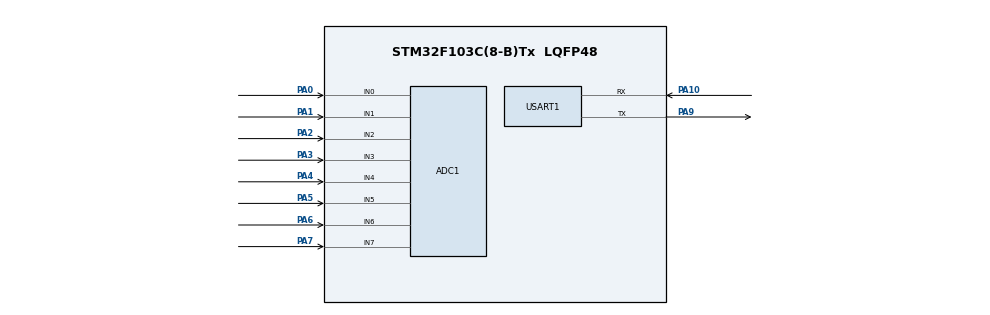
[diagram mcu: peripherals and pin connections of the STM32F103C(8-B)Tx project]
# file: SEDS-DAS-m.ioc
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ADC1.Channel=ADC_CHANNEL_6
ADC1.Channel-1\#ChannelRegularConversion=ADC_CHANNEL_0
ADC1.Channel-2\#ChannelRegularConversion=ADC_CHANNEL_0
ADC1.Channel-3\#ChannelRegularConversion=ADC_CHANNEL_0
ADC1.Channel-4\#ChannelRegularConversion=ADC_CHANNEL_0
ADC1.Channel-5\#ChannelRegularConversion=ADC_CHANNEL_0
ADC1.Channel-6\#ChannelRegularConversion=ADC_CHANNEL_0
ADC1.Channel-7\#ChannelRegularConversion=ADC_CHANNEL_0
ADC1.Channel-8\#ChannelRegularConversion=ADC_CHANNEL_0
ADC1.ContinuousConvMode=DISABLE
ADC1.EnableRegularConversion=ENABLE
ADC1.NbrOfConversion=8
ADC1.NbrOfConversionFlag=1
ADC1.Rank-1\#ChannelRegularConversion=1
ADC1.Rank-2\#ChannelRegularConversion=2
ADC1.Rank-3\#ChannelRegularConversion=3
ADC1.Rank-4\#ChannelRegularConversion=4
ADC1.Rank-5\#ChannelRegularConversion=5
ADC1.Rank-6\#ChannelRegularConversion=6
ADC1.Rank-7\#ChannelRegularConversion=7
ADC1.Rank-8\#ChannelRegularConversion=8
ADC1.SamplingTime-1\#ChannelRegularConversion=ADC_SAMPLETIME_1CYCLE_5
ADC1.SamplingTime-2\#ChannelRegularConversion=ADC_SAMPLETIME_1CYCLE_5
ADC1.SamplingTime-3\#ChannelRegularConversion=ADC_SAMPLETIME_1CYCLE_5
ADC1.SamplingTime-4\#ChannelRegularConversion=ADC_SAMPLETIME_1CYCLE_5
ADC1.SamplingTime-5\#ChannelRegularConversion=ADC_SAMPLETIME_1CYCLE_5
ADC1.SamplingTime-6\#ChannelRegularConversion=ADC_SAMPLETIME_1CYCLE_5
ADC1.SamplingTime-7\#ChannelRegularConversion=ADC_SAMPLETIME_1CYCLE_5
ADC1.SamplingTime-8\#ChannelRegularConversion=ADC_SAMPLETIME_1CYCLE_5
ADC1.master=1
Dma.ADC1.0.Direction=DMA_PERIPH_TO_MEMORY
Dma.ADC1.0.Instance=DMA1_Channel1
Dma.ADC1.0.MemDataAlignment=DMA_MDATAALIGN_BYTE
Dma.ADC1.0.MemInc=DMA_MINC_DISABLE
Dma.ADC1.0.Mode=DMA_NORMAL
Dma.ADC1.0.PeriphDataAlignment=DMA_PDATAALIGN_BYTE
Dma.ADC1.0.PeriphInc=DMA_PINC_DISABLE
Dma.ADC1.0.Priority=DMA_PRIORITY_LOW
Dma.Request0=ADC1
FREERTOS.Tasks01=defaultTask,0,128,StartDefaultTask;pingBack,0,128,StartTask02;idleADCSample,-3,128,StartTask03
Mcu.Family=STM32F1
Mcu.Name=STM32F103C(8-B)Tx
Mcu.Package=LQFP48
NVIC.ADC1_2_IRQn=true\:5\:0\:false
NVIC.DMA1_Channel1_IRQn=true\:5\:0\:false
NVIC.PriorityGroup=NVIC_PRIORITYGROUP_4
NVIC.TIM1_UP_IRQn=true\:5\:0\:false
PA0-WKUP.Signal=ADCx_IN0
PA1.Signal=ADCx_IN1
PA10.Mode=Asynchronous
PA10.Signal=USART1_RX
PA2.Signal=ADCx_IN2
PA3.Signal=ADCx_IN3
PA4.Signal=ADCx_IN4
PA5.Signal=ADCx_IN5
PA6.Signal=ADCx_IN6
PA7.Signal=ADCx_IN7
PA9.Mode=Asynchronous
PA9.Signal=USART1_TX
ProjectManager.TargetToolchain=MDK-ARM 4.73
RCC.ADCPresc=RCC_ADCPCLK2_DIV6
RCC.AHBFreq_Value=64000000
RCC.APB1CLKDivider=RCC_HCLK_DIV2
RCC.APB1Freq_Value=32000000
RCC.APB1TimFreq_Value=64000000
RCC.APB2Freq_Value=64000000
RCC.APB2TimFreq_Value=64000000
RCC.HCLKFreq_Value=64000000
RCC.SYSCLKFreq_VALUE=64000000
RCC.SYSCLKSource=RCC_SYSCLKSOURCE_PLLCLK
RCC.USBFreq_Value=64000000
SH.ADCx_IN0.0=ADC1_IN0,IN0
SH.ADCx_IN1.0=ADC1_IN1,IN1
SH.ADCx_IN2.0=ADC1_IN2,IN2
SH.ADCx_IN3.0=ADC1_IN3,IN3
SH.ADCx_IN4.0=ADC1_IN4,IN4
SH.ADCx_IN5.0=ADC1_IN5,IN5
SH.ADCx_IN6.0=ADC1_IN6,IN6
SH.ADCx_IN7.0=ADC1_IN7,IN7
TIM1.Period=50000
USART1.Parity-Asynchronous=UART_PARITY_EVEN
USART1.WordLength-Asynchronous=UART_WORDLENGTH_9B
VP_FREERTOS_VS_ENABLE.Mode=Enabled
VP_TIM1_VS_ClockSourceINT.Mode=Internal

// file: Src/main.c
/**
  ******************************************************************************
  * File Name          : main.c
  * Date               : 04/04/2015 04:53:10
  * Description        : Main program body
  ******************************************************************************
  *
  * COPYRIGHT(c) 2015 STMicroelectronics
  *
  * Redistribution and use in source and binary forms, with or without modification,
  * are permitted provided that the following conditions are met:
  *   1. Redistributions of source code must retain the above copyright notice,
  *      this list of conditions and the following disclaimer.
  *   2. Redistributions in binary form must reproduce the above copyright notice,
  *      this list of conditions and the following disclaimer in the documentation
  *      and/or other materials provided with the distribution.
  *   3. Neither the name of STMicroelectronics nor the names of its contributors
  *      may be used to endorse or promote products derived from this software
  *      without specific prior written permission.
  *
  * THIS SOFTWARE IS PROVIDED BY THE COPYRIGHT HOLDERS AND CONTRIBUTORS "AS IS"
  * AND ANY EXPRESS OR IMPLIED WARRANTIES, INCLUDING, BUT NOT LIMITED TO, THE
  * IMPLIED WARRANTIES OF MERCHANTABILITY AND FITNESS FOR A PARTICULAR PURPOSE ARE
  * DISCLAIMED. IN NO EVENT SHALL THE COPYRIGHT HOLDER OR CONTRIBUTORS BE LIABLE
  * FOR ANY DIRECT, INDIRECT, INCIDENTAL, SPECIAL, EXEMPLARY, OR CONSEQUENTIAL
  * DAMAGES (INCLUDING, BUT NOT LIMITED TO, PROCUREMENT OF SUBSTITUTE GOODS OR
  * SERVICES; LOSS OF USE, DATA, OR PROFITS; OR BUSINESS INTERRUPTION) HOWEVER
  * CAUSED AND ON ANY THEORY OF LIABILITY, WHETHER IN CONTRACT, STRICT LIABILITY,
  * OR TORT (INCLUDING NEGLIGENCE OR OTHERWISE) ARISING IN ANY WAY OUT OF THE USE
  * OF THIS SOFTWARE, EVEN IF ADVISED OF THE POSSIBILITY OF SUCH DAMAGE.
  *
  ******************************************************************************
  */

#include "stm32f1xx_hal.h"
#include "cmsis_os.h"

ADC_HandleTypeDef hadc1;
DMA_HandleTypeDef hdma_adc1;

TIM_HandleTypeDef htim1;

UART_HandleTypeDef huart1;

osThreadId defaultTaskHandle;
osThreadId pingBackHandle;
osThreadId idleADCSampleHandle;

void SystemClock_Config(void);
static void MX_GPIO_Init(void);
static void MX_DMA_Init(void);
static void MX_ADC1_Init(void);
static void MX_TIM1_Init(void);
static void MX_USART1_UART_Init(void);
void StartDefaultTask(void const * argument);
void StartTask02(void const * argument);
void StartTask03(void const * argument);

int main(void)
{

  /* MCU Configuration----------------------------------------------------------*/

  /* Reset of all peripherals, Initializes the Flash interface and the Systick. */
  HAL_Init();

  /* Configure the system clock */
  SystemClock_Config();

  /* Initialize all configured peripherals */
  MX_GPIO_Init();
  MX_DMA_Init();
  MX_ADC1_Init();
  MX_TIM1_Init();
  MX_USART1_UART_Init();

  /* Create the thread(s) */
  /* definition and creation of defaultTask */
  osThreadDef(defaultTask, StartDefaultTask, osPriorityNormal, 0, 128);
  defaultTaskHandle = osThreadCreate(osThread(defaultTask), NULL);

  /* definition and creation of pingBack */
  osThreadDef(pingBack, StartTask02, osPriorityNormal, 0, 128);
  pingBackHandle = osThreadCreate(osThread(pingBack), NULL);

  /* definition and creation of idleADCSample */
  osThreadDef(idleADCSample, StartTask03, osPriorityIdle, 0, 128);
  idleADCSampleHandle = osThreadCreate(osThread(idleADCSample), NULL);

  /* Start scheduler */
  osKernelStart();

  /* We should never get here as control is now taken by the scheduler */

  while (1)
  {
  }

}

/** System Clock Configuration
*/
void SystemClock_Config(void)
{

  RCC_OscInitTypeDef RCC_OscInitStruct;
  RCC_ClkInitTypeDef RCC_ClkInitStruct;
  RCC_PeriphCLKInitTypeDef PeriphClkInit;

  RCC_OscInitStruct.OscillatorType = RCC_OSCILLATORTYPE_HSI;
  RCC_OscInitStruct.HSIState = RCC_HSI_ON;
  RCC_OscInitStruct.HSICalibrationValue = 16;
  RCC_OscInitStruct.PLL.PLLState = RCC_PLL_ON;
  RCC_OscInitStruct.PLL.PLLSource = RCC_PLLSOURCE_HSI_DIV2;
  RCC_OscInitStruct.PLL.PLLMUL = RCC_PLL_MUL2;
  HAL_RCC_OscConfig(&RCC_OscInitStruct);

  RCC_ClkInitStruct.ClockType = RCC_CLOCKTYPE_SYSCLK|RCC_CLOCKTYPE_PCLK1;
  RCC_ClkInitStruct.SYSCLKSource = RCC_SYSCLKSOURCE_PLLCLK;
  RCC_ClkInitStruct.AHBCLKDivider = RCC_SYSCLK_DIV1;
  RCC_ClkInitStruct.APB1CLKDivider = RCC_HCLK_DIV2;
  RCC_ClkInitStruct.APB2CLKDivider = RCC_HCLK_DIV1;
  HAL_RCC_ClockConfig(&RCC_ClkInitStruct, FLASH_LATENCY_2);

  PeriphClkInit.PeriphClockSelection = RCC_PERIPHCLK_ADC;
  PeriphClkInit.AdcClockSelection = RCC_ADCPCLK2_DIV6;
  HAL_RCCEx_PeriphCLKConfig(&PeriphClkInit);

  __HAL_RCC_AFIO_CLK_ENABLE();

}

/* ADC1 init function */
void MX_ADC1_Init(void)
{

  ADC_ChannelConfTypeDef sConfig;

    /**Common config
    */
  hadc1.Instance = ADC1;
  hadc1.Init.ScanConvMode = ENABLE;
  hadc1.Init.ContinuousConvMode = DISABLE;
  hadc1.Init.DiscontinuousConvMode = DISABLE;
  hadc1.Init.ExternalTrigConv = ADC_SOFTWARE_START;
  hadc1.Init.DataAlign = ADC_DATAALIGN_RIGHT;
  hadc1.Init.NbrOfConversion = 8;
  HAL_ADC_Init(&hadc1);

    /**Configure Regular Channel
    */
  sConfig.Channel = ADC_CHANNEL_0;
  sConfig.Rank = 1;
  sConfig.SamplingTime = ADC_SAMPLETIME_1CYCLE_5;
  HAL_ADC_ConfigChannel(&hadc1, &sConfig);

    /**Configure Regular Channel
    */
  sConfig.Rank = 2;
  HAL_ADC_ConfigChannel(&hadc1, &sConfig);

    /**Configure Regular Channel
    */
  sConfig.Rank = 3;
  HAL_ADC_ConfigChannel(&hadc1, &sConfig);

    /**Configure Regular Channel
    */
  sConfig.Rank = 4;
  HAL_ADC_ConfigChannel(&hadc1, &sConfig);

    /**Configure Regular Channel
    */
  sConfig.Rank = 5;
  HAL_ADC_ConfigChannel(&hadc1, &sConfig);

    /**Configure Regular Channel
    */
  sConfig.Rank = 6;
  HAL_ADC_ConfigChannel(&hadc1, &sConfig);

    /**Configure Regular Channel
    */
  sConfig.Rank = 7;
  HAL_ADC_ConfigChannel(&hadc1, &sConfig);

    /**Configure Regular Channel
    */
  sConfig.Rank = 8;
  HAL_ADC_ConfigChannel(&hadc1, &sConfig);

}

/* TIM1 init function */
void MX_TIM1_Init(void)
{

  TIM_ClockConfigTypeDef sClockSourceConfig;
  TIM_MasterConfigTypeDef sMasterConfig;

  htim1.Instance = TIM1;
  htim1.Init.Prescaler = 0;
  htim1.Init.CounterMode = TIM_COUNTERMODE_UP;
  htim1.Init.Period = 50000;
  htim1.Init.ClockDivision = TIM_CLOCKDIVISION_DIV1;
  htim1.Init.RepetitionCounter = 0;
  HAL_TIM_Base_Init(&htim1);

  sClockSourceConfig.ClockSource = TIM_CLOCKSOURCE_INTERNAL;
  HAL_TIM_ConfigClockSource(&htim1, &sClockSourceConfig);

  sMasterConfig.MasterOutputTrigger = TIM_TRGO_RESET;
  sMasterConfig.MasterSlaveMode = TIM_MASTERSLAVEMODE_DISABLE;
  HAL_TIMEx_MasterConfigSynchronization(&htim1, &sMasterConfig);

}

/* USART1 init function */
void MX_USART1_UART_Init(void)
{

  huart1.Instance = USART1;
  huart1.Init.BaudRate = 115200;
  huart1.Init.WordLength = UART_WORDLENGTH_9B;
  huart1.Init.StopBits = UART_STOPBITS_1;
  huart1.Init.Parity = UART_PARITY_EVEN;
  huart1.Init.Mode = UART_MODE_TX_RX;
  huart1.Init.HwFlowCtl = UART_HWCONTROL_NONE;
  huart1.Init.OverSampling = UART_OVERSAMPLING_16;
  HAL_UART_Init(&huart1);
	//USART_InitStructure.USART_BaudRate = 9600;

}

void MX_DMA_Init(void)
{
  /* DMA controller clock enable */
  __HAL_RCC_DMA1_CLK_ENABLE();

  /* DMA interrupt init */
  HAL_NVIC_SetPriority(DMA1_Channel1_IRQn, 5, 0);
  HAL_NVIC_EnableIRQ(DMA1_Channel1_IRQn);

}

/** Pinout Configuration
*/
void MX_GPIO_Init(void)
{

  /* GPIO Ports Clock Enable */
  __GPIOA_CLK_ENABLE();

}

void StartDefaultTask(void const * argument)
{

  for(;;)
  {
    osDelay(1);
  }

}

/* StartTask02 function */
void StartTask02(void const * argument)
{
  /* USER CODE BEGIN StartTask02 */
  /* Infinite loop */
  for(;;)
  {
    osDelay(1);
		ARM_USART_Send	(	"12345",67890 );
  }
  /* USER CODE END StartTask02 */
}

/* StartTask03 function */
void StartTask03(void const * argument)
{
  for(;;)
  {
    osDelay(1);
  }
}

/************************ (C) COPYRIGHT STMicroelectronics *****END OF FILE****/
